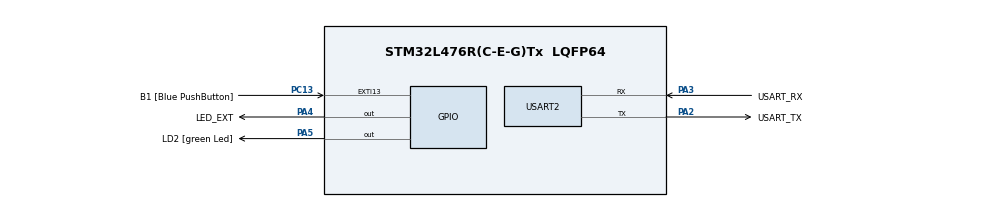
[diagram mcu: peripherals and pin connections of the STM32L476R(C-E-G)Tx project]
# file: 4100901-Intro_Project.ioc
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Mcu.Family=STM32L4
Mcu.Name=STM32L476R(C-E-G)Tx
Mcu.Package=LQFP64
NVIC.PriorityGroup=NVIC_PRIORITYGROUP_4
PA13\ (JTMS-SWDIO).GPIO_Label=TMS
PA13\ (JTMS-SWDIO).Mode=Serial_Wire
PA13\ (JTMS-SWDIO).Signal=SYS_JTMS-SWDIO
PA14\ (JTCK-SWCLK).GPIO_Label=TCK
PA14\ (JTCK-SWCLK).Mode=Serial_Wire
PA14\ (JTCK-SWCLK).Signal=SYS_JTCK-SWCLK
PA2.GPIO_Label=USART_TX
PA2.GPIO_Mode=GPIO_MODE_AF_PP
PA2.GPIO_PuPd=GPIO_NOPULL
PA2.GPIO_Speed=GPIO_SPEED_FREQ_VERY_HIGH
PA2.Mode=Asynchronous
PA2.Signal=USART2_TX
PA3.GPIO_Label=USART_RX
PA3.GPIO_Mode=GPIO_MODE_AF_PP
PA3.GPIO_PuPd=GPIO_NOPULL
PA3.GPIO_Speed=GPIO_SPEED_FREQ_VERY_HIGH
PA3.Mode=Asynchronous
PA3.Signal=USART2_RX
PA4.GPIO_Label=LED_EXT
PA4.Signal=GPIO_Output
PA5.GPIO_Label=LD2 [green Led]
PA5.GPIO_ModeDefaultOutputPP=GPIO_MODE_OUTPUT_PP
PA5.GPIO_PuPd=GPIO_NOPULL
PA5.GPIO_Speed=GPIO_SPEED_FREQ_LOW
PA5.Signal=GPIO_Output
PB3\ (JTDO-TRACESWO).GPIO_Label=SWO
PB3\ (JTDO-TRACESWO).Signal=SYS_JTDO-SWO
PC13.GPIO_Label=B1 [Blue PushButton]
PC13.GPIO_ModeDefaultEXTI=GPIO_MODE_IT_FALLING
PC13.GPIO_PuPd=GPIO_NOPULL
PC13.Signal=GPXTI13
PC14-OSC32_IN\ (PC14).Mode=LSE-External-Oscillator
PC14-OSC32_IN\ (PC14).Signal=RCC_OSC32_IN
PC15-OSC32_OUT\ (PC15).Mode=LSE-External-Oscillator
PC15-OSC32_OUT\ (PC15).Signal=RCC_OSC32_OUT
PH0-OSC_IN\ (PH0).Signal=RCC_OSC_IN
PH1-OSC_OUT\ (PH1).Signal=RCC_OSC_OUT
ProjectManager.HeapSize=0x200
ProjectManager.StackSize=0x400
ProjectManager.TargetToolchain=CMake
RCC.ADCFreq_Value=16000000
RCC.AHBFreq_Value=16000000
RCC.APB1Freq_Value=16000000
RCC.APB1TimFreq_Value=16000000
RCC.APB2Freq_Value=16000000
RCC.APB2TimFreq_Value=16000000
RCC.CortexFreq_Value=16000000
RCC.HCLKFreq_Value=16000000
RCC.HSE_VALUE=8000000
RCC.HSI_VALUE=16000000
RCC.MSI_VALUE=4000000
RCC.PLLN=40
RCC.PREFETCH_ENABLE=1
RCC.SYSCLKFreq_VALUE=16000000
RCC.SYSCLKSource=RCC_SYSCLKSOURCE_HSI
RCC.USBFreq_Value=16000000
RCC.VCOOutputFreq_Value=160000000
USART2.VirtualMode-Asynchronous=VM_ASYNC
board=NUCLEO-L476RG

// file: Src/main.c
/* USER CODE BEGIN Header */
/**
  ******************************************************************************
  * @file           : main.c
  * @brief          : Main program body
  ******************************************************************************
  * @attention
  *
  * Copyright (c) 2025 STMicroelectronics.
  * All rights reserved.
  *
  * This software is licensed under terms that can be found in the LICENSE file
  * in the root directory of this software component.
  * If no LICENSE file comes with this software, it is provided AS-IS.
  *
  ******************************************************************************
  */
/* USER CODE END Header */

#include "main.h"
#include "usart.h"
#include "gpio.h"

/* USER CODE BEGIN Includes */
#include <stdio.h>
#include <string.h>
/* USER CODE END Includes */

/* USER CODE BEGIN PV */
uint8_t rx_data;
char tx_buffer[50];
volatile uint8_t button_flag = 0;
volatile uint32_t led_ext_off_time = 0;
/* USER CODE END PV */

void SystemClock_Config(void);

/* USER CODE BEGIN 0 */
void HAL_UART_RxCpltCallback(UART_HandleTypeDef *huart)
{
  if (huart->Instance == USART2)
  {
    HAL_UART_Transmit(&huart2, &rx_data, 1, 10);
    HAL_UART_Receive_IT(&huart2, &rx_data, 1);
  }
}
/* USER CODE END 0 */

int main(void)
{
  HAL_Init();
  SystemClock_Config();
  MX_GPIO_Init();
  MX_USART2_UART_Init();

  /* USER CODE BEGIN 2 */
  HAL_UART_Receive_IT(&huart2, &rx_data, 1);
  char *welcome_msg = "Sistema de Control Basico - Listo\r\n";
  HAL_UART_Transmit(&huart2, (uint8_t*)welcome_msg, strlen(welcome_msg), 100);
  /* USER CODE END 2 */

  /* Infinite loop */
  while (1)
  {
    /* USER CODE BEGIN 3 */
    // Procesamiento del botón
    if (button_flag == 1)
    {
      // Encender ambos LEDs
      HAL_GPIO_WritePin(LED_EXT_GPIO_Port, LED_EXT_Pin, GPIO_PIN_SET); // LED externo
      HAL_GPIO_WritePin(LD2_GPIO_Port, LD2_Pin, GPIO_PIN_SET);         // LD2

      // Programar apagado del LED externo
      led_ext_off_time = HAL_GetTick() + 1000; // 1 segundo

      // Mensaje UART
      sprintf(tx_buffer, "Boton B1 presionado! LED Externo ON, LD2 ON.\r\n");
      HAL_UART_Transmit(&huart2, (uint8_t*)tx_buffer, strlen(tx_buffer), 100);

      button_flag = 0;
    }

    // Apagado automático del LED externo
    if (led_ext_off_time != 0 && HAL_GetTick() >= led_ext_off_time)
    {
      HAL_GPIO_WritePin(LED_EXT_GPIO_Port, LED_EXT_Pin, GPIO_PIN_RESET);
      sprintf(tx_buffer, "LED EXT OFF (timeout).\r\n");
      HAL_UART_Transmit(&huart2, (uint8_t*)tx_buffer, strlen(tx_buffer), 100);
      led_ext_off_time = 0;
    }
    /* USER CODE END 3 */
  }
}

void SystemClock_Config(void)
{
  RCC_OscInitTypeDef RCC_OscInitStruct = {0};
  RCC_ClkInitTypeDef RCC_ClkInitStruct = {0};

  if (HAL_PWREx_ControlVoltageScaling(PWR_REGULATOR_VOLTAGE_SCALE1) != HAL_OK) Error_Handler();

  HAL_PWR_EnableBkUpAccess();
  __HAL_RCC_LSEDRIVE_CONFIG(RCC_LSEDRIVE_LOW);

  RCC_OscInitStruct.OscillatorType = RCC_OSCILLATORTYPE_LSE|RCC_OSCILLATORTYPE_MSI;
  RCC_OscInitStruct.LSEState = RCC_LSE_ON;
  RCC_OscInitStruct.MSIState = RCC_MSI_ON;
  RCC_OscInitStruct.MSICalibrationValue = 0;
  RCC_OscInitStruct.MSIClockRange = RCC_MSIRANGE_6;
  RCC_OscInitStruct.PLL.PLLState = RCC_PLL_ON;
  RCC_OscInitStruct.PLL.PLLSource = RCC_PLLSOURCE_MSI;
  RCC_OscInitStruct.PLL.PLLM = 1;
  RCC_OscInitStruct.PLL.PLLN = 40;
  RCC_OscInitStruct.PLL.PLLP = RCC_PLLP_DIV7;
  RCC_OscInitStruct.PLL.PLLQ = RCC_PLLQ_DIV2;
  RCC_OscInitStruct.PLL.PLLR = RCC_PLLR_DIV2;
  if (HAL_RCC_OscConfig(&RCC_OscInitStruct) != HAL_OK) Error_Handler();

  RCC_ClkInitStruct.ClockType = RCC_CLOCKTYPE_HCLK|RCC_CLOCKTYPE_SYSCLK
                              |RCC_CLOCKTYPE_PCLK1|RCC_CLOCKTYPE_PCLK2;
  RCC_ClkInitStruct.SYSCLKSource = RCC_SYSCLKSOURCE_PLLCLK;
  RCC_ClkInitStruct.AHBCLKDivider = RCC_SYSCLK_DIV1;
  RCC_ClkInitStruct.APB1CLKDivider = RCC_HCLK_DIV1;
  RCC_ClkInitStruct.APB2CLKDivider = RCC_HCLK_DIV1;

  if (HAL_RCC_ClockConfig(&RCC_ClkInitStruct, FLASH_LATENCY_4) != HAL_OK) Error_Handler();

  HAL_RCCEx_EnableMSIPLLMode();
}

/* USER CODE BEGIN 4 */
void HAL_GPIO_EXTI_Callback(uint16_t GPIO_Pin)
{
  static uint32_t last_press_time = 0;
  uint32_t current_time = HAL_GetTick();

  if (GPIO_Pin == B1_Pin)
  {
    if (current_time - last_press_time > 200)
    {
      button_flag = 1;
      last_press_time = current_time;
    }
  }
}
/* USER CODE END 4 */

void Error_Handler(void)
{
  __disable_irq();
  while (1) {}
}
